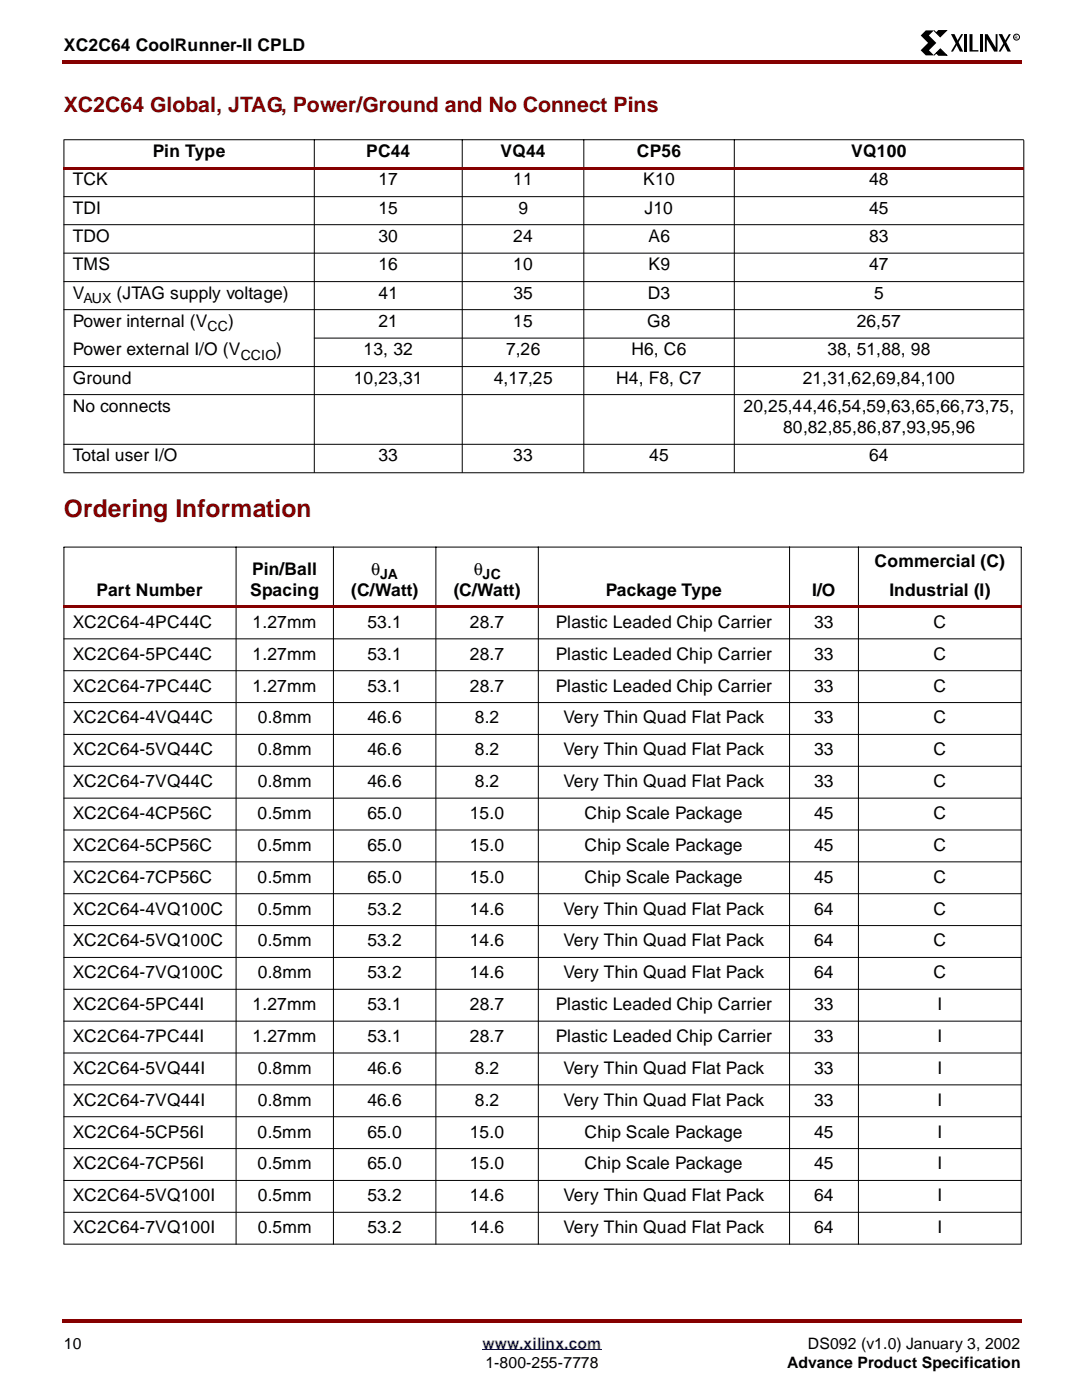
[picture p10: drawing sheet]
<svg xmlns="http://www.w3.org/2000/svg" width="216mm" height="279mm" viewBox="0 0 216 279" stroke-linecap="round" stroke-linejoin="round" font-family="sans-serif">
<defs><g id="words">
<text font-size="4.9" fill="#850000" x="12.7" y="103.1">Ordering Information</text>
<text font-size="4.2" fill="#850000" x="12.7" y="22.3">XC2C64 Global, JTAG, Power/Ground and No Connect Pins</text>
<g font-size="3.5">
<text x="12.7" y="10.2">XC2C64 CoolRunner-II CPLD</text>
<text x="30.4" y="31.3">Pin Type</text>
<text x="72.9" y="31.3">PC44</text>
<text x="99.7" y="31.3">VQ44</text>
<text x="126.9" y="31.3">CP56</text>
<text x="169.5" y="31.3">VQ100</text>
<text x="14.5" y="36.9">TCK</text>
<text x="75.4" y="36.9">17</text>
<text x="102.2" y="36.9">11</text>
<text x="128.1" y="36.9">K10</text>
<text x="173.1" y="36.9">48</text>
<text x="14.5" y="42.6">TDI</text>
<text x="75.4" y="42.6">15</text>
<text x="103.2" y="42.6">9</text>
<text x="128.4" y="42.6">J10</text>
<text x="173.1" y="42.6">45</text>
<text x="14.5" y="48.3">TDO</text>
<text x="14.5" y="53.8">TMS</text>
<text x="75.4" y="48.3">30</text>
<text x="75.4" y="53.8">16</text>
<text x="102.2" y="48.3">24</text>
<text x="102.2" y="53.8">10</text>
<text x="129.1" y="48.3">A6</text>
<text x="129.1" y="53.8">K9</text>
<text x="173.1" y="48.3">83</text>
<text x="173.1" y="53.8">47</text>
<text x="14.5" y="59.5">V</text>
<text x="23.2" y="59.5">(JTAG supply voltage)</text>
<text x="75.4" y="59.5">41</text>
<text x="102.2" y="59.5">35</text>
<text x="129" y="59.5">D3</text>
<text x="174.1" y="59.5">5</text>
<text x="14.5" y="65.2">Power internal (V</text>
<text x="45.4" y="65.2">)</text>
<text x="75.4" y="65.2">21</text>
<text x="102.2" y="65.2">15</text>
<text x="128.9" y="65.2">G8</text>
<text x="170.6" y="65.2">26,57</text>
<text x="14.5" y="70.8">Power external I/O (V</text>
<text x="55" y="70.8">)</text>
<text x="72.4" y="70.8">13, 32</text>
<text x="100.8" y="70.8">7,26</text>
<text x="125.8" y="70.8">H6, C6</text>
<text x="164.8" y="70.8">38, 51,88, 98</text>
<text x="14.5" y="76.5">Ground</text>
<text x="70.5" y="76.5">10,23,31</text>
<text x="98.3" y="76.5">4,17,25</text>
<text x="122.7" y="76.5">H4, F8, C7</text>
<text x="159.9" y="76.5">21,31,62,69,84,100</text>
<text x="14.5" y="82.1">No connects</text>
<text x="148.1" y="82.1">20,25,44,46,54,59,63,65,66,73,75,</text>
<text x="156" y="86.4">80,82,85,86,87,93,95,96</text>
<text x="14.5" y="91.9">Total user I/O</text>
<text x="75.4" y="91.9">33</text>
<text x="102.2" y="91.9">33</text>
<text x="129.3" y="91.9">45</text>
<text x="173.1" y="91.9">64</text>
<text x="174.2" y="113.1">Commercial (C)</text>
<text x="19.3" y="118.8">Part Number</text>
<text x="49.8" y="118.8">Spacing</text>
<text x="50.2" y="114.6">Pin/Ball</text>
<text x="70" y="118.8">(C/Watt)</text>
<text x="73.9" y="114.6">θ</text>
<text x="90.4" y="118.8">(C/Watt)</text>
<text x="94.4" y="114.6">θ</text>
<text x="120.7" y="118.8">Package Type</text>
<text x="161.7" y="118.8">I/O</text>
<text x="177.2" y="118.8">Industrial (I)</text>
<text x="14.5" y="125.1">XC2C64-4PC44C</text>
<text x="50.3" y="125.1">1.27mm</text>
<text x="73.2" y="125.1">53.1</text>
<text x="93.6" y="125.1">28.7</text>
<text x="110.7" y="125.1">Plastic Leaded Chip Carrier</text>
<text x="162.2" y="125.1">33</text>
<text x="186" y="125.1">C</text>
<text x="14.5" y="131.5">XC2C64-5PC44C</text>
<text x="50.3" y="131.5">1.27mm</text>
<text x="73.2" y="131.5">53.1</text>
<text x="93.6" y="131.5">28.7</text>
<text x="110.7" y="131.5">Plastic Leaded Chip Carrier</text>
<text x="162.2" y="131.5">33</text>
<text x="186" y="131.5">C</text>
<text x="14.5" y="137.8">XC2C64-7PC44C</text>
<text x="50.3" y="137.8">1.27mm</text>
<text x="73.2" y="137.8">53.1</text>
<text x="93.6" y="137.8">28.7</text>
<text x="110.7" y="137.8">Plastic Leaded Chip Carrier</text>
<text x="162.2" y="137.8">33</text>
<text x="186" y="137.8">C</text>
<text x="14.5" y="144.2">XC2C64-4VQ44C</text>
<text x="51.3" y="144.2">0.8mm</text>
<text x="73.2" y="144.2">46.6</text>
<text x="94.6" y="144.2">8.2</text>
<text x="112.2" y="144.2">Very Thin Quad Flat Pack</text>
<text x="162.2" y="144.2">33</text>
<text x="186" y="144.2">C</text>
<text x="14.5" y="150.5">XC2C64-5VQ44C</text>
<text x="51.3" y="150.5">0.8mm</text>
<text x="73.2" y="150.5">46.6</text>
<text x="94.6" y="150.5">8.2</text>
<text x="112.2" y="150.5">Very Thin Quad Flat Pack</text>
<text x="162.2" y="150.5">33</text>
<text x="186" y="150.5">C</text>
<text x="14.5" y="156.9">XC2C64-7VQ44C</text>
<text x="51.3" y="156.9">0.8mm</text>
<text x="73.2" y="156.9">46.6</text>
<text x="94.6" y="156.9">8.2</text>
<text x="112.2" y="156.9">Very Thin Quad Flat Pack</text>
<text x="162.2" y="156.9">33</text>
<text x="186" y="156.9">C</text>
<text x="14.5" y="163.2">XC2C64-4CP56C</text>
<text x="51.3" y="163.2">0.5mm</text>
<text x="73.2" y="163.2">65.0</text>
<text x="93.6" y="163.2">15.0</text>
<text x="116.4" y="163.2">Chip Scale Package</text>
<text x="162.2" y="163.2">45</text>
<text x="186" y="163.2">C</text>
<text x="14.5" y="169.6">XC2C64-5CP56C</text>
<text x="51.3" y="169.6">0.5mm</text>
<text x="73.2" y="169.6">65.0</text>
<text x="93.6" y="169.6">15.0</text>
<text x="116.4" y="169.6">Chip Scale Package</text>
<text x="162.2" y="169.6">45</text>
<text x="186" y="169.6">C</text>
<text x="14.5" y="175.9">XC2C64-7CP56C</text>
<text x="51.3" y="175.9">0.5mm</text>
<text x="73.2" y="175.9">65.0</text>
<text x="93.6" y="175.9">15.0</text>
<text x="116.4" y="175.9">Chip Scale Package</text>
<text x="162.2" y="175.9">45</text>
<text x="186" y="175.9">C</text>
<text x="14.5" y="182.3">XC2C64-4VQ100C</text>
<text x="51.3" y="182.3">0.5mm</text>
<text x="73.2" y="182.3">53.2</text>
<text x="93.6" y="182.3">14.6</text>
<text x="112.2" y="182.3">Very Thin Quad Flat Pack</text>
<text x="162.2" y="182.3">64</text>
<text x="186" y="182.3">C</text>
<text x="14.5" y="188.6">XC2C64-5VQ100C</text>
<text x="51.3" y="188.6">0.5mm</text>
<text x="73.2" y="188.6">53.2</text>
<text x="93.6" y="188.6">14.6</text>
<text x="112.2" y="188.6">Very Thin Quad Flat Pack</text>
<text x="162.2" y="188.6">64</text>
<text x="186" y="188.6">C</text>
<text x="14.5" y="195">XC2C64-7VQ100C</text>
<text x="51.3" y="195">0.8mm</text>
<text x="73.2" y="195">53.2</text>
<text x="93.6" y="195">14.6</text>
<text x="112.2" y="195">Very Thin Quad Flat Pack</text>
<text x="162.2" y="195">64</text>
<text x="186" y="195">C</text>
<text x="14.5" y="201.3">XC2C64-5PC44I</text>
<text x="50.3" y="201.3">1.27mm</text>
<text x="73.2" y="201.3">53.1</text>
<text x="93.6" y="201.3">28.7</text>
<text x="110.7" y="201.3">Plastic Leaded Chip Carrier</text>
<text x="162.2" y="201.3">33</text>
<text x="186.7" y="201.3">I</text>
<text x="14.5" y="207.7">XC2C64-7PC44I</text>
<text x="50.3" y="207.7">1.27mm</text>
<text x="73.2" y="207.7">53.1</text>
<text x="93.6" y="207.7">28.7</text>
<text x="110.7" y="207.7">Plastic Leaded Chip Carrier</text>
<text x="162.2" y="207.7">33</text>
<text x="186.7" y="207.7">I</text>
<text x="14.5" y="214">XC2C64-5VQ44I</text>
<text x="51.3" y="214">0.8mm</text>
<text x="73.2" y="214">46.6</text>
<text x="94.6" y="214">8.2</text>
<text x="112.2" y="214">Very Thin Quad Flat Pack</text>
<text x="162.2" y="214">33</text>
<text x="186.7" y="214">I</text>
<text x="14.5" y="220.4">XC2C64-7VQ44I</text>
<text x="51.3" y="220.4">0.8mm</text>
<text x="73.2" y="220.4">46.6</text>
<text x="94.6" y="220.4">8.2</text>
<text x="112.2" y="220.4">Very Thin Quad Flat Pack</text>
<text x="162.2" y="220.4">33</text>
<text x="186.7" y="220.4">I</text>
<text x="14.5" y="226.7">XC2C64-5CP56I</text>
<text x="51.3" y="226.7">0.5mm</text>
<text x="73.2" y="226.7">65.0</text>
<text x="93.6" y="226.7">15.0</text>
<text x="116.4" y="226.7">Chip Scale Package</text>
<text x="162.2" y="226.7">45</text>
<text x="186.7" y="226.7">I</text>
<text x="14.5" y="233.1">XC2C64-7CP56I</text>
<text x="51.3" y="233.1">0.5mm</text>
<text x="73.2" y="233.1">65.0</text>
<text x="93.6" y="233.1">15.0</text>
<text x="116.4" y="233.1">Chip Scale Package</text>
<text x="162.2" y="233.1">45</text>
<text x="186.7" y="233.1">I</text>
<text x="14.5" y="239.4">XC2C64-5VQ100I</text>
<text x="51.3" y="239.4">0.5mm</text>
<text x="73.2" y="239.4">53.2</text>
<text x="93.6" y="239.4">14.6</text>
<text x="112.2" y="239.4">Very Thin Quad Flat Pack</text>
<text x="162.2" y="239.4">64</text>
<text x="186.7" y="239.4">I</text>
<text x="14.5" y="245.8">XC2C64-7VQ100I</text>
<text x="51.3" y="245.8">0.5mm</text>
<text x="73.2" y="245.8">53.2</text>
<text x="93.6" y="245.8">14.6</text>
<text x="112.2" y="245.8">Very Thin Quad Flat Pack</text>
<text x="162.2" y="245.8">64</text>
<text x="186.7" y="245.8">I</text>
</g>
<g font-size="3.1">
<text x="12.7" y="268.8">10</text>
<text x="160.9" y="268.8">DS092 (v1.0) January 3, 2002</text>
<text x="96.7" y="272.7">1-800-255-7778</text>
<text x="156.7" y="272.7">Advance Product Specification</text>
</g>
<text font-size="3.1" fill="#00f" x="96.1" y="268.8">www.xilinx.com</text>
<g font-size="2.8">
<text x="16.6" y="60.4">AUX</text>
<text x="41.3" y="66">CC</text>
<text x="48" y="71.7">CCIO</text>
<text x="75.7" y="115.4">JA</text>
<text x="96.1" y="115.4">JC</text>
</g>
<text font-size=".9" x="202.1" y="7.7">R</text>
</g></defs>
<g fill="#850000">
<path d="M12.4 12h.3v.7h-.3z"/>
<path d="M203.2 12h.4v.7h-.4z"/>
<path d="M12.7 12h190.5v.7h-190.5z"/>
</g>
<path d="M12.7 266.7h190.4v7.6h-190.4z" fill="#fff"/>
<path d="M96.1 269.1h23.7" fill="none" stroke="#00f" stroke-width=".2"/>
<g fill="#850000">
<path d="M12.4 262.9h.3v.7h-.3z"/>
<path d="M203.2 262.9h.4v.7h-.4z"/>
<path d="M12.7 262.9h190.5v.7h-190.5z"/>
</g>
<path d="M183.2 6h19.9v5.2h-19.9z" fill="#fff"/>
<path d="M183.4 7.1l1-1h1.6l-1 1 1.5 1.5-1.5 1.4 1 1h-1.6l-1-1 1.4-1.5zM189.4 6.8h.7l1.7 3.5h-.6zM191.4 6.8h.4l-2 3.5h-.4zM192 6.8h.6v3.5h-.6zM193.1 6.8h.6v3.2h1.2v.3h-1.8zM195.1 6.8h.6v3.5h-.6zM196.2 6.8h.5l1.6 2.7v-2.7h.4v3.5h-.7l-1.5-2.5v2.5h-.3zM198.9 6.8h.7l1.7 3.5h-.6zM200.9 6.8h.4l-2 3.5h-.4z" fill="#000"/>
<path d="M186 6.1l.5 .4 .4-.4h1.6l-1.2 1.2zM186.5 10.6l-.5 .4 1.3-1.3 1.3 1.3h-1.7z" fill="#000" stroke="#000" stroke-width=".2"/>
<g fill="none" stroke="#000" stroke-width=".2">
<path d="M12.6 27.9h191.3M12.7 27.9v66.2M62.6 27.9v66.3M92.1 27.9v66.3M116.3 27.9v66.3M146.3 27.9v66.3M203.9 27.9v66.2"/>
<circle cx="202.5" cy="7.4" r=".59"/>
</g>
<path d="M12.6 33.3h191.3v.5h-191.3z" fill="#850000"/>
<g fill="none" stroke="#000" stroke-width=".2">
<path d="M12.6 39.2h191.3M12.6 44.8h191.3M12.6 50.5h191.3M12.6 56.1h191.3M12.6 61.7h191.3M12.6 73.1h191.3M12.6 78.7h191.3M62.5 67.4h141.4M12.6 88.6h191.3M12.6 94.2h191.3M12.6 109h190.9M12.7 109v139"/>
<path d="M47 109v139.1M66.4 109v139.1M86.8 109v139.1M107.2 109v139.1M157.3 109v139.1M171 109v139.1M203.4 109v139"/>
</g>
<path d="M12.6 120.7h190.9v.5h-190.9z" fill="#850000"/>
<g fill="none" stroke="#000" stroke-width=".2">
<path d="M12.6 127.3h190.9M12.6 133.7h190.9M12.6 140h190.9M12.6 146.4h190.9M12.6 152.7h190.9M12.6 159.1h190.9M12.6 165.4h190.9M12.6 171.8h190.9M12.6 178.1h190.9M12.6 184.5h190.9M12.6 190.8h190.9M12.6 197.2h190.9"/>
<path d="M12.6 203.5h190.9M12.6 209.9h190.9M12.6 216.2h190.9M12.6 222.6h190.9M12.6 228.9h190.9M12.6 235.3h190.9M12.6 241.6h190.9M12.6 248h190.9"/>
</g>
<use href="#words"/>
</svg>
